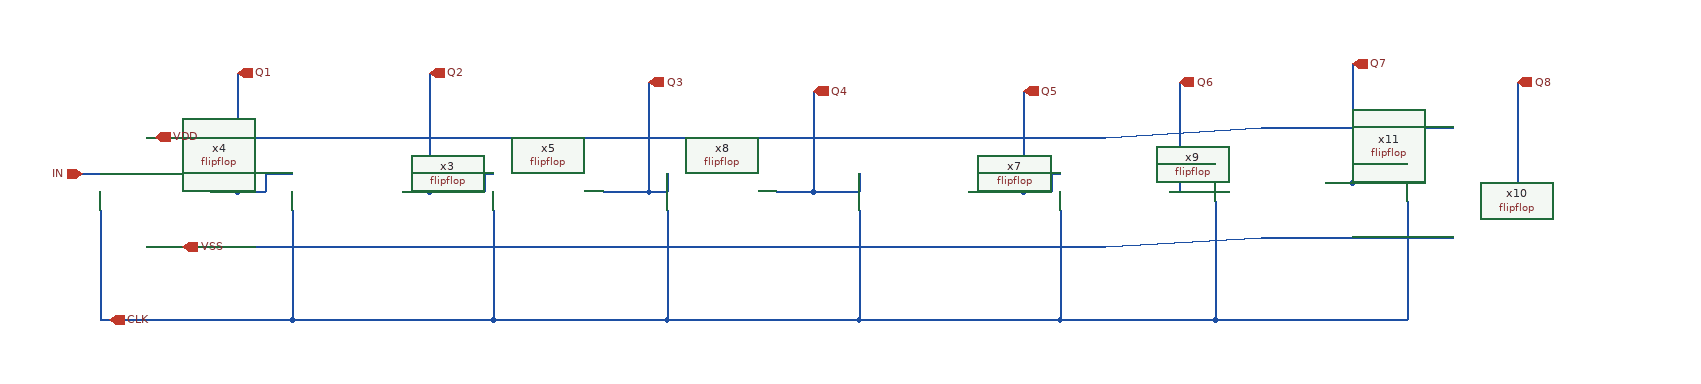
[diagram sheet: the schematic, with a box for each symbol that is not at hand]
v {xschem version=3.4.6 file_version=1.2}
G {}
K {}
V {}
S {}
E {}
N -20 -0 10 -0 {lab=Q1}
N 10 -20 10 -0 {lab=Q1}
N 10 -20 40 -20 {lab=Q1}
N -120 -60 930 -60 {lab=VDD}
N -120 60 930 60 {lab=VSS}
N 190 -0 250 0 {lab=Q2}
N 250 -20 250 0 {lab=Q2}
N 250 -20 260 -20 {lab=Q2}
N 840 0 870 0 {lab=Q5}
N 870 -20 870 0 {lab=Q5}
N 870 -20 880 -20 {lab=Q5}
N 430 0 450 0 {lab=Q3}
N 450 -20 450 0 {lab=Q3}
N 1200 -10 1230 -10 {lab=Q7}
N 1230 -30 1230 -10 {lab=Q7}
N 1230 -30 1260 -30 {lab=Q7}
N 40 20 40 140 {lab=CLK}
N 260 20 260 140 {lab=CLK}
N 40 140 260 140 {lab=CLK}
N 450 20 450 140 {lab=CLK}
N 260 140 450 140 {lab=CLK}
N 660 20 660 140 {lab=CLK}
N 450 140 660 140 {lab=CLK}
N 880 20 880 140 {lab=CLK}
N 660 140 880 140 {lab=CLK}
N 1050 10 1050 140 {lab=CLK}
N 880 140 1050 140 {lab=CLK}
N 1260 10 1260 140 {lab=CLK}
N 1050 140 1260 140 {lab=CLK}
N 930 -60 1100 -70 {lab=VDD}
N 930 60 1100 50 {lab=VSS}
N 190 -130 190 -0 {lab=Q2}
N 160 0 190 -0 {lab=Q2}
N 430 -120 430 0 {lab=Q3}
N 380 0 430 0 {lab=Q3}
N 840 -110 840 0 {lab=Q5}
N 780 0 840 0 {lab=Q5}
N 1100 50 1310 50 {lab=VSS}
N 1100 -70 1310 -70 {lab=VDD}
N 1010 -30 1010 0 {lab=Q6}
N 1000 -0 1010 0 {lab=Q6}
N 1200 -140 1200 -10 {lab=Q7}
N 1170 -10 1200 -10 {lab=Q7}
N 1380 -120 1380 -10 {lab=Q8}
N -190 -20 -170 -20 {lab=IN}
N -170 140 40 140 {lab=CLK}
N -170 20 -170 140 {lab=CLK}
N -20 -130 -20 -0 {lab=Q1}
N -50 0 -20 -0 {lab=Q1}
N 610 -0 660 -0 {lab=Q4}
N 660 -20 660 -0 {lab=Q4}
N 610 -110 610 -0 {lab=Q4}
N 570 0 610 -0 {lab=Q4}
N 1010 -30 1050 -30 {lab=Q6}
N 1010 -120 1010 -30 {lab=Q6}
C {/home/designer/shared/flipflop.sym} 210 0 0 0 {name=x3}
C {/home/designer/shared/flipflop.sym} 0 0 0 0 {name=x4}
C {/home/designer/shared/flipflop.sym} 430 0 0 0 {name=x5}
C {/home/designer/shared/flipflop.sym} 830 0 0 0 {name=x7}
C {/home/designer/shared/flipflop.sym} 620 0 0 0 {name=x8}
C {/home/designer/shared/flipflop.sym} 1050 0 0 0 {name=x9}
C {/home/designer/shared/flipflop.sym} 1430 -10 0 0 {name=x10}
C {/home/designer/shared/flipflop.sym} 1220 -10 0 0 {name=x11}
C {ipin.sym} -190 -20 0 0 {name=p1 lab=IN}
C {opin.sym} -20 -130 0 0 {name=p2 lab=Q1}
C {iopin.sym} -160 140 0 1 {name=p4 lab=CLK
}
C {iopin.sym} -110 -60 0 1 {name=p3 lab=VDD
}
C {iopin.sym} -80 60 0 1 {name=p6 lab=VSS
}
C {opin.sym} 190 -130 0 0 {name=p5 lab=Q2}
C {opin.sym} 430 -120 0 0 {name=p7 lab=Q3}
C {opin.sym} 610 -110 0 0 {name=p8 lab=Q4}
C {opin.sym} 840 -110 0 0 {name=p9 lab=Q5}
C {opin.sym} 1010 -120 0 0 {name=p10 lab=Q6}
C {opin.sym} 1200 -140 0 0 {name=p11 lab=Q7}
C {opin.sym} 1380 -120 0 0 {name=p12 lab=Q8}
